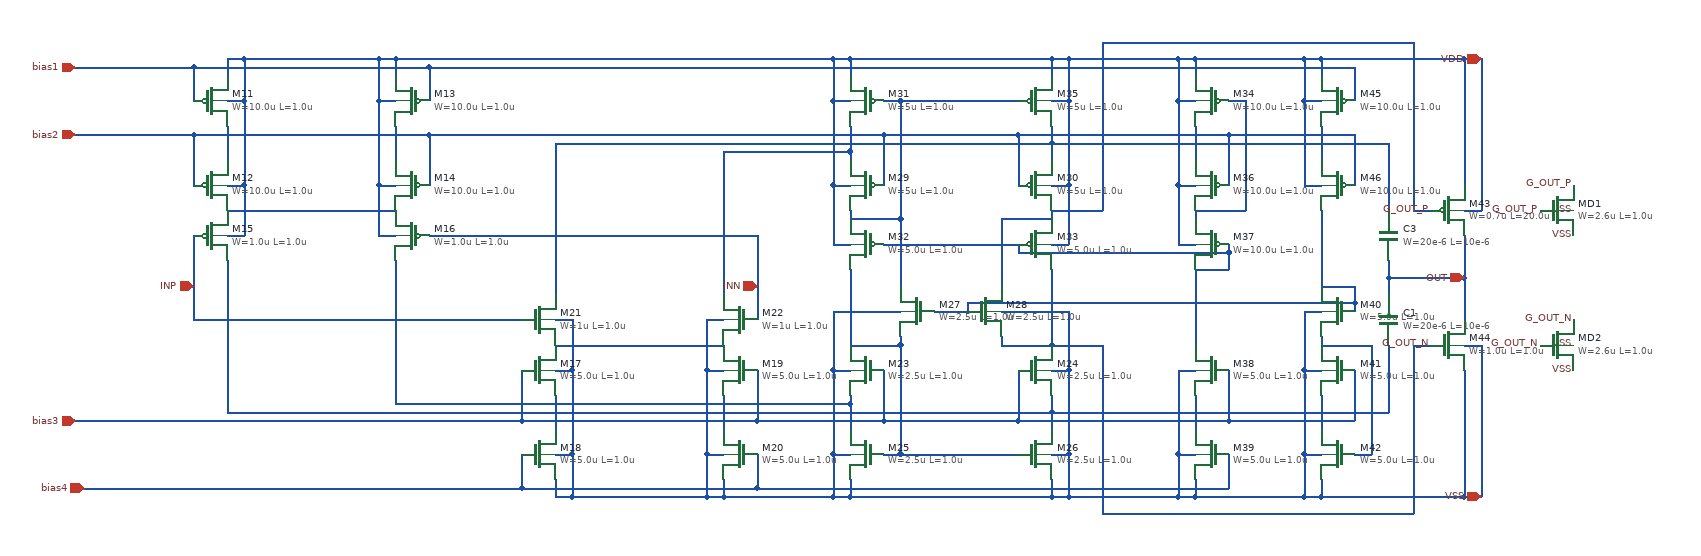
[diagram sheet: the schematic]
v {xschem version=3.4.8RC file_version=1.3}
G {}
K {}
V {}
S {}
F {}
E {}
N -580 -460 -560 -460 {
lab=VDD}
N -400 -460 -380 -460 {
lab=VDD}
N -580 -670 -580 -650 {
lab=VDD}
N -580 -620 -560 -620 {
lab=VDD}
N -620 -660 -620 -620 {
lab=bias1}
N 140 -200 140 -150 {
lab=VSS}
N 140 -200 160 -200 {
lab=VSS}
N 160 -170 160 -150 {
lab=VSS}
N 160 -670 160 -650 {
lab=VDD}
N 140 -620 160 -620 {
lab=VDD}
N 400 -670 400 -650 {
lab=VDD}
N 400 -620 420 -620 {
lab=VDD}
N 420 -620 420 -520 {
lab=VDD}
N 400 -200 420 -200 {
lab=VSS}
N 400 -170 400 -150 {
lab=VSS}
N -620 -460 -620 -360 {
lab=INP}
N -10 -360 10 -360 {
lab=VSS}
N -190 -300 -170 -300 {
lab=VSS}
N -170 -200 -170 -150 {
lab=VSS}
N -190 -200 -170 -200 {
lab=VSS}
N -190 -270 -190 -230 {
lab=#net1}
N -190 -170 -190 -150 {
lab=VSS}
N -230 -200 -230 -160 {
lab=#net2}
N -230 -300 -230 -240 {
lab=bias3}
N -580 -520 -560 -520 {
lab=VDD}
N -580 -590 -580 -550 {
lab=#net3}
N -620 -580 -620 -520 {
lab=bias2}
N 140 -620 140 -520 {
lab=VDD}
N 140 -520 160 -520 {
lab=VDD}
N 160 -560 160 -550 {
lab=#net4}
N 140 -300 160 -300 {
lab=VSS}
N 140 -300 140 -200 {
lab=VSS}
N 160 -260 160 -230 {
lab=#net5}
N 400 -250 400 -230 {
lab=#net6}
N 400 -300 420 -300 {
lab=VSS}
N -340 -460 50 -460 {
lab=INN}
N 50 -460 50 -360 {
lab=INN}
N 400 -520 420 -520 {
lab=VDD}
N 400 -570 400 -550 {
lab=#net7}
N -580 -490 -380 -490 {
lab=#net8}
N -620 -360 -230 -360 {
lab=INP}
N -190 -330 10 -330 {
lab=#net9}
N 160 -490 160 -480 {
lab=#net10}
N 140 -450 160 -450 {
lab=VDD}
N 140 -520 140 -450 {
lab=VDD}
N 220 -200 360 -200 {
lab=#net11}
N 420 -200 420 -150 {
lab=VSS}
N 260 -370 300 -370 {
lab=#net12}
N 400 -450 420 -450 {
lab=VDD}
N 420 -520 420 -450 {
lab=VDD}
N 400 -490 400 -480 {
lab=#net13}
N 340 -370 420 -370 {
lab=VSS}
N 420 -370 420 -300 {
lab=VSS}
N 890 -410 890 -360 {
lab=OUT}
N 890 -490 910 -490 {
lab=VDD}
N 910 -670 910 -490 {
lab=VDD}
N 570 -670 700 -670 {
lab=VDD}
N 890 -330 910 -330 {
lab=VSS}
N 910 -330 910 -150 {
lab=VSS}
N 890 -300 890 -150 {
lab=VSS}
N 890 -670 890 -520 {
lab=VDD}
N 550 -620 570 -620 {
lab=VDD}
N 550 -670 550 -620 {
lab=VDD}
N 570 -670 570 -650 {
lab=VDD}
N 570 -590 570 -550 {
lab=#net14}
N 550 -520 570 -520 {
lab=VDD}
N 550 -620 550 -520 {
lab=VDD}
N 570 -490 570 -480 {
lab=#net15}
N 550 -450 570 -450 {
lab=VDD}
N 550 -520 550 -450 {
lab=VDD}
N 550 -300 570 -300 {
lab=VSS}
N 550 -200 550 -150 {
lab=VSS}
N 550 -200 570 -200 {
lab=VSS}
N 570 -270 570 -230 {
lab=#net16}
N 570 -170 570 -150 {
lab=VSS}
N 610 -200 610 -160 {
lab=#net2}
N 610 -300 610 -240 {
lab=bias3}
N 700 -620 720 -620 {
lab=VDD}
N 700 -670 700 -620 {
lab=VDD}
N 720 -670 720 -650 {
lab=VDD}
N 720 -590 720 -550 {
lab=#net17}
N 700 -520 720 -520 {
lab=VDD}
N 700 -620 700 -520 {
lab=VDD}
N 700 -300 720 -300 {
lab=VSS}
N 700 -200 700 -150 {
lab=VSS}
N 700 -200 720 -200 {
lab=VSS}
N 720 -270 720 -230 {
lab=#net18}
N 720 -170 720 -150 {
lab=VSS}
N 720 -340 720 -330 {
lab=#net19}
N 700 -370 720 -370 {
lab=VSS}
N 700 -370 700 -300 {
lab=VSS}
N 720 -670 890 -670 {
lab=VDD}
N -380 -670 -380 -650 {
lab=VDD}
N -400 -620 -380 -620 {
lab=VDD}
N -340 -660 -340 -620 {
lab=bias1}
N -400 -520 -380 -520 {
lab=VDD}
N -380 -590 -380 -550 {
lab=#net20}
N -340 -580 -340 -520 {
lab=bias2}
N -10 -300 10 -300 {
lab=VSS}
N -10 -200 10 -200 {
lab=VSS}
N 10 -270 10 -230 {
lab=#net21}
N 10 -170 10 -150 {
lab=VSS}
N 50 -200 50 -160 {
lab=#net2}
N 50 -300 50 -240 {
lab=bias3}
N -190 -360 -170 -360 {
lab=VSS}
N 610 -580 610 -520 {
lab=bias2}
N 610 -620 630 -620 {
lab=#net15}
N 630 -620 630 -490 {
lab=#net15}
N 570 -490 630 -490 {
lab=#net15}
N 610 -440 610 -420 {
lab=#net22}
N 570 -420 610 -420 {
lab=#net22}
N 570 -420 570 -330 {
lab=#net22}
N 760 -660 760 -620 {
lab=bias1}
N 760 -580 760 -520 {
lab=bias2}
N 360 -240 610 -240 {
lab=bias3}
N 760 -300 760 -240 {
lab=bias3}
N 760 -200 780 -200 {
lab=#net19}
N 780 -330 780 -200 {
lab=#net19}
N 720 -330 780 -330 {
lab=#net19}
N 760 -380 760 -370 {
lab=#net12}
N 720 -400 760 -400 {
lab=#net12}
N 720 -490 720 -400 {
lab=#net12}
N 220 -620 360 -620 {
lab=#net10}
N 200 -580 200 -520 {
lab=bias2}
N 360 -580 360 -520 {
lab=bias2}
N 200 -450 360 -450 {
lab=#net22}
N 160 -420 160 -330 {
lab=#net11}
N 220 -340 220 -330 {
lab=#net11}
N 160 -330 220 -330 {
lab=#net11}
N 340 -340 340 -330 {
lab=#net23}
N 340 -330 400 -330 {
lab=#net23}
N 140 -370 220 -370 {
lab=VSS}
N 140 -370 140 -300 {
lab=VSS}
N 400 -420 400 -330 {
lab=#net23}
N 220 -480 220 -400 {
lab=#net10}
N 160 -480 220 -480 {
lab=#net10}
N 340 -480 340 -400 {
lab=#net13}
N 340 -480 400 -480 {
lab=#net13}
N 610 -580 760 -580 {
lab=bias2}
N 50 -160 610 -160 {
lab=#net2}
N 610 -240 760 -240 {
lab=bias3}
N 360 -440 610 -440 {
lab=#net22}
N 360 -450 360 -440 {
lab=#net22}
N 300 -380 760 -380 {
lab=#net12}
N 300 -380 300 -370 {
lab=#net12}
N -580 -430 -580 -250 {
lab=#net6}
N -380 -430 -380 -260 {
lab=#net5}
N -190 -570 -190 -390 {
lab=#net7}
N 10 -560 10 -390 {
lab=#net4}
N 200 -300 200 -240 {
lab=bias3}
N 360 -300 360 -240 {
lab=bias3}
N 220 -330 220 -200 {
lab=#net11}
N 220 -620 220 -480 {
lab=#net10}
N 890 -670 910 -670 {
lab=VDD}
N 830 -490 850 -490 {
lab=#net13}
N 830 -690 830 -490 {
lab=#net13}
N 460 -690 830 -690 {
lab=#net13}
N 460 -690 460 -490 {
lab=#net13}
N 400 -490 460 -490 {
lab=#net13}
N 830 -330 850 -330 {
lab=#net23}
N 830 -330 830 -130 {
lab=#net23}
N 460 -130 830 -130 {
lab=#net23}
N 460 -330 460 -130 {
lab=#net23}
N 400 -330 460 -330 {
lab=#net23}
N 400 -250 800 -250 {
lab=#net6}
N 800 -410 800 -390 {
lab=OUT}
N -190 -570 400 -570 {
lab=#net7}
N 10 -560 160 -560 {
lab=#net4}
N -380 -260 160 -260 {
lab=#net5}
N -580 -250 400 -250 {
lab=#net6}
N 140 -670 160 -670 {
lab=VDD}
N 400 -670 420 -670 {
lab=VDD}
N 890 -150 910 -150 {
lab=VSS}
N -230 -240 50 -240 {
lab=bias3}
N -230 -160 50 -160 {
lab=#net2}
N -620 -660 -340 -660 {
lab=bias1}
N -620 -580 -340 -580 {
lab=bias2}
N 360 -580 610 -580 {
lab=bias2}
N -340 -660 760 -660 {
lab=bias1}
N -400 -670 -380 -670 {
lab=VDD}
N -770 -660 -620 -660 {
lab=bias1}
N -770 -580 -620 -580 {
lab=bias2}
N -770 -240 -230 -240 {
lab=bias3}
N -750 -160 -230 -160 {
lab=#net2}
N 800 -410 890 -410 {
lab=OUT}
N 800 -330 800 -250 {
lab=#net6}
N 400 -570 800 -570 {
lab=#net7}
N 800 -570 800 -490 {
lab=#net7}
N 800 -430 800 -410 {
lab=OUT}
N -400 -620 -400 -520 {
lab=VDD}
N -560 -620 -560 -520 {
lab=VDD}
N -10 -200 -10 -150 {
lab=VSS}
N -170 -360 -170 -300 {
lab=VSS}
N -10 -360 -10 -300 {
lab=VSS}
N -560 -520 -560 -460 {
lab=VDD}
N -400 -520 -400 -460 {
lab=VDD}
N -560 -670 -560 -620 {
lab=VDD}
N 10 -150 140 -150 {
lab=VSS}
N 140 -150 160 -150 {
lab=VSS}
N 140 -670 140 -620 {
lab=VDD}
N 160 -670 400 -670 {
lab=VDD}
N 420 -670 420 -620 {
lab=VDD}
N 420 -300 420 -200 {
lab=VSS}
N 160 -150 400 -150 {
lab=VSS}
N -190 -150 -170 -150 {
lab=VSS}
N -170 -300 -170 -200 {
lab=VSS}
N 400 -150 420 -150 {
lab=VSS}
N 720 -150 890 -150 {
lab=VSS}
N 420 -670 550 -670 {
lab=VDD}
N 550 -670 570 -670 {
lab=VDD}
N 420 -150 550 -150 {
lab=VSS}
N 550 -300 550 -200 {
lab=VSS}
N 550 -150 570 -150 {
lab=VSS}
N 700 -670 720 -670 {
lab=VDD}
N 570 -150 700 -150 {
lab=VSS}
N 700 -300 700 -200 {
lab=VSS}
N 700 -150 720 -150 {
lab=VSS}
N -400 -670 -400 -620 {
lab=VDD}
N -10 -300 -10 -200 {
lab=VSS}
N -10 -150 10 -150 {
lab=VSS}
N -340 -580 200 -580 {
lab=bias2}
N 200 -580 360 -580 {
lab=bias2}
N 610 -450 610 -440 {
lab=#net22}
N 760 -400 760 -380 {
lab=#net12}
N 50 -240 200 -240 {
lab=bias3}
N 200 -240 360 -240 {
lab=bias3}
N 200 -200 220 -200 {
lab=#net11}
N 200 -620 220 -620 {
lab=#net10}
N 400 -270 400 -250 {
lab=#net6}
N 400 -590 400 -570 {
lab=#net7}
N 160 -590 160 -560 {
lab=#net4}
N 160 -270 160 -260 {
lab=#net5}
N 890 -460 890 -410 {
lab=OUT}
N -170 -150 -10 -150 {
lab=VSS}
N -580 -670 -560 -670 {
lab=VDD}
N -380 -670 140 -670 {
lab=VDD}
N -560 -670 -400 -670 {
lab=VDD}
C {ipin.sym} 50 -400 2 0 {name=p1 lab=INN}
C {ipin.sym} -620 -400 0 0 {name=p2 lab=INP}
C {iopin.sym} 910 -670 0 0 {name=p3 lab=VDD}
C {iopin.sym} 910 -150 0 0 {name=p4 lab=VSS}
C {iopin.sym} 890 -410 0 0 {name=p5 lab=OUT}
C {symbols/pfet_06v0.sym} -600 -620 0 0 {name=M11
L=1.0u
W=10.0u
nf=1
m=1
ad="'int((nf+1)/2) * W/nf * 0.18u'"
pd="'2*int((nf+1)/2) * (W/nf + 0.18u)'"
as="'int((nf+2)/2) * W/nf * 0.18u'"
ps="'2*int((nf+2)/2) * (W/nf + 0.18u)'"
nrd="'0.18u / W'" nrs="'0.18u / W'"
sa=0 sb=0 sd=0
model=pfet_06v0
spiceprefix=X
}
C {symbols/pfet_06v0.sym} -600 -520 0 0 {name=M12
L=1.0u
W=10.0u
nf=1
m=1
ad="'int((nf+1)/2) * W/nf * 0.18u'"
pd="'2*int((nf+1)/2) * (W/nf + 0.18u)'"
as="'int((nf+2)/2) * W/nf * 0.18u'"
ps="'2*int((nf+2)/2) * (W/nf + 0.18u)'"
nrd="'0.18u / W'" nrs="'0.18u / W'"
sa=0 sb=0 sd=0
model=pfet_06v0
spiceprefix=X
}
C {symbols/pfet_06v0.sym} -360 -620 0 1 {name=M13
L=1.0u
W=10.0u
nf=1
m=1
ad="'int((nf+1)/2) * W/nf * 0.18u'"
pd="'2*int((nf+1)/2) * (W/nf + 0.18u)'"
as="'int((nf+2)/2) * W/nf * 0.18u'"
ps="'2*int((nf+2)/2) * (W/nf + 0.18u)'"
nrd="'0.18u / W'" nrs="'0.18u / W'"
sa=0 sb=0 sd=0
model=pfet_06v0
spiceprefix=X
}
C {symbols/pfet_06v0.sym} -360 -520 0 1 {name=M14
L=1.0u
W=10.0u
nf=1
m=1
ad="'int((nf+1)/2) * W/nf * 0.18u'"
pd="'2*int((nf+1)/2) * (W/nf + 0.18u)'"
as="'int((nf+2)/2) * W/nf * 0.18u'"
ps="'2*int((nf+2)/2) * (W/nf + 0.18u)'"
nrd="'0.18u / W'" nrs="'0.18u / W'"
sa=0 sb=0 sd=0
model=pfet_06v0
spiceprefix=X
}
C {symbols/pfet_06v0.sym} -600 -460 0 0 {name=M15
L=1.0u
W=1.0u
nf=1
m=1
ad="'int((nf+1)/2) * W/nf * 0.18u'"
pd="'2*int((nf+1)/2) * (W/nf + 0.18u)'"
as="'int((nf+2)/2) * W/nf * 0.18u'"
ps="'2*int((nf+2)/2) * (W/nf + 0.18u)'"
nrd="'0.18u / W'" nrs="'0.18u / W'"
sa=0 sb=0 sd=0
model=pfet_06v0
spiceprefix=X
}
C {symbols/pfet_06v0.sym} -360 -460 0 1 {name=M16
L=1.0u
W=1.0u
nf=1
m=1
ad="'int((nf+1)/2) * W/nf * 0.18u'"
pd="'2*int((nf+1)/2) * (W/nf + 0.18u)'"
as="'int((nf+2)/2) * W/nf * 0.18u'"
ps="'2*int((nf+2)/2) * (W/nf + 0.18u)'"
nrd="'0.18u / W'" nrs="'0.18u / W'"
sa=0 sb=0 sd=0
model=pfet_06v0
spiceprefix=X
}
C {symbols/nfet_06v0.sym} -210 -300 0 0 {name=M17
L=1.0u
W=5.0u
nf=1
m=1
ad="'int((nf+1)/2) * W/nf * 0.18u'"
pd="'2*int((nf+1)/2) * (W/nf + 0.18u)'"
as="'int((nf+2)/2) * W/nf * 0.18u'"
ps="'2*int((nf+2)/2) * (W/nf + 0.18u)'"
nrd="'0.18u / W'" nrs="'0.18u / W'"
sa=0 sb=0 sd=0
model=nfet_06v0
spiceprefix=X
}
C {symbols/nfet_06v0.sym} -210 -200 0 0 {name=M18
L=1.0u
W=5.0u
nf=1
m=1
ad="'int((nf+1)/2) * W/nf * 0.18u'"
pd="'2*int((nf+1)/2) * (W/nf + 0.18u)'"
as="'int((nf+2)/2) * W/nf * 0.18u'"
ps="'2*int((nf+2)/2) * (W/nf + 0.18u)'"
nrd="'0.18u / W'" nrs="'0.18u / W'"
sa=0 sb=0 sd=0
model=nfet_06v0
spiceprefix=X
}
C {symbols/nfet_06v0.sym} 30 -300 0 1 {name=M19
L=1.0u
W=5.0u
nf=1
m=1
ad="'int((nf+1)/2) * W/nf * 0.18u'"
pd="'2*int((nf+1)/2) * (W/nf + 0.18u)'"
as="'int((nf+2)/2) * W/nf * 0.18u'"
ps="'2*int((nf+2)/2) * (W/nf + 0.18u)'"
nrd="'0.18u / W'" nrs="'0.18u / W'"
sa=0 sb=0 sd=0
model=nfet_06v0
spiceprefix=X
}
C {symbols/nfet_06v0.sym} 30 -200 0 1 {name=M20
L=1.0u
W=5.0u
nf=1
m=1
ad="'int((nf+1)/2) * W/nf * 0.18u'"
pd="'2*int((nf+1)/2) * (W/nf + 0.18u)'"
as="'int((nf+2)/2) * W/nf * 0.18u'"
ps="'2*int((nf+2)/2) * (W/nf + 0.18u)'"
nrd="'0.18u / W'" nrs="'0.18u / W'"
sa=0 sb=0 sd=0
model=nfet_06v0
spiceprefix=X
}
C {symbols/nfet_06v0.sym} -210 -360 0 0 {name=M21
L=1.0u
W=1u
nf=1
m=1
ad="'int((nf+1)/2) * W/nf * 0.18u'"
pd="'2*int((nf+1)/2) * (W/nf + 0.18u)'"
as="'int((nf+2)/2) * W/nf * 0.18u'"
ps="'2*int((nf+2)/2) * (W/nf + 0.18u)'"
nrd="'0.18u / W'" nrs="'0.18u / W'"
sa=0 sb=0 sd=0
model=nfet_06v0
spiceprefix=X
}
C {symbols/nfet_06v0.sym} 30 -360 0 1 {name=M22
L=1.0u
W=1u
nf=1
m=1
ad="'int((nf+1)/2) * W/nf * 0.18u'"
pd="'2*int((nf+1)/2) * (W/nf + 0.18u)'"
as="'int((nf+2)/2) * W/nf * 0.18u'"
ps="'2*int((nf+2)/2) * (W/nf + 0.18u)'"
nrd="'0.18u / W'" nrs="'0.18u / W'"
sa=0 sb=0 sd=0
model=nfet_06v0
spiceprefix=X
}
C {symbols/pfet_06v0.sym} 180 -520 0 1 {name=M29
L=1.0u
W=5u
nf=1
m=1
ad="'int((nf+1)/2) * W/nf * 0.18u'"
pd="'2*int((nf+1)/2) * (W/nf + 0.18u)'"
as="'int((nf+2)/2) * W/nf * 0.18u'"
ps="'2*int((nf+2)/2) * (W/nf + 0.18u)'"
nrd="'0.18u / W'" nrs="'0.18u / W'"
sa=0 sb=0 sd=0
model=pfet_06v0
spiceprefix=X
}
C {symbols/pfet_06v0.sym} 380 -520 0 0 {name=M30
L=1.0u
W=5u
nf=1
m=1
ad="'int((nf+1)/2) * W/nf * 0.18u'"
pd="'2*int((nf+1)/2) * (W/nf + 0.18u)'"
as="'int((nf+2)/2) * W/nf * 0.18u'"
ps="'2*int((nf+2)/2) * (W/nf + 0.18u)'"
nrd="'0.18u / W'" nrs="'0.18u / W'"
sa=0 sb=0 sd=0
model=pfet_06v0
spiceprefix=X
}
C {symbols/pfet_06v0.sym} 180 -620 0 1 {name=M31
L=1.0u
W=5u
nf=1
m=1
ad="'int((nf+1)/2) * W/nf * 0.18u'"
pd="'2*int((nf+1)/2) * (W/nf + 0.18u)'"
as="'int((nf+2)/2) * W/nf * 0.18u'"
ps="'2*int((nf+2)/2) * (W/nf + 0.18u)'"
nrd="'0.18u / W'" nrs="'0.18u / W'"
sa=0 sb=0 sd=0
model=pfet_06v0
spiceprefix=X
}
C {symbols/pfet_06v0.sym} 380 -620 0 0 {name=M35
L=1.0u
W=5u
nf=1
m=1
ad="'int((nf+1)/2) * W/nf * 0.18u'"
pd="'2*int((nf+1)/2) * (W/nf + 0.18u)'"
as="'int((nf+2)/2) * W/nf * 0.18u'"
ps="'2*int((nf+2)/2) * (W/nf + 0.18u)'"
nrd="'0.18u / W'" nrs="'0.18u / W'"
sa=0 sb=0 sd=0
model=pfet_06v0
spiceprefix=X
}
C {symbols/pfet_06v0.sym} 180 -450 0 1 {name=M32
L=1.0u
W=5.0u
nf=1
m=1
ad="'int((nf+1)/2) * W/nf * 0.18u'"
pd="'2*int((nf+1)/2) * (W/nf + 0.18u)'"
as="'int((nf+2)/2) * W/nf * 0.18u'"
ps="'2*int((nf+2)/2) * (W/nf + 0.18u)'"
nrd="'0.18u / W'" nrs="'0.18u / W'"
sa=0 sb=0 sd=0
model=pfet_06v0
spiceprefix=X
}
C {symbols/pfet_06v0.sym} 380 -450 0 0 {name=M33
L=1.0u
W=5.0u
nf=1
m=1
ad="'int((nf+1)/2) * W/nf * 0.18u'"
pd="'2*int((nf+1)/2) * (W/nf + 0.18u)'"
as="'int((nf+2)/2) * W/nf * 0.18u'"
ps="'2*int((nf+2)/2) * (W/nf + 0.18u)'"
nrd="'0.18u / W'" nrs="'0.18u / W'"
sa=0 sb=0 sd=0
model=pfet_06v0
spiceprefix=X
}
C {symbols/nfet_06v0.sym} 180 -300 0 1 {name=M23
L=1.0u
W=2.5u
nf=1
m=1
ad="'int((nf+1)/2) * W/nf * 0.18u'"
pd="'2*int((nf+1)/2) * (W/nf + 0.18u)'"
as="'int((nf+2)/2) * W/nf * 0.18u'"
ps="'2*int((nf+2)/2) * (W/nf + 0.18u)'"
nrd="'0.18u / W'" nrs="'0.18u / W'"
sa=0 sb=0 sd=0
model=nfet_06v0
spiceprefix=X
}
C {symbols/nfet_06v0.sym} 380 -300 0 0 {name=M24
L=1.0u
W=2.5u
nf=1
m=1
ad="'int((nf+1)/2) * W/nf * 0.18u'"
pd="'2*int((nf+1)/2) * (W/nf + 0.18u)'"
as="'int((nf+2)/2) * W/nf * 0.18u'"
ps="'2*int((nf+2)/2) * (W/nf + 0.18u)'"
nrd="'0.18u / W'" nrs="'0.18u / W'"
sa=0 sb=0 sd=0
model=nfet_06v0
spiceprefix=X
}
C {symbols/nfet_06v0.sym} 180 -200 0 1 {name=M25
L=1.0u
W=2.5u
nf=1
m=1
ad="'int((nf+1)/2) * W/nf * 0.18u'"
pd="'2*int((nf+1)/2) * (W/nf + 0.18u)'"
as="'int((nf+2)/2) * W/nf * 0.18u'"
ps="'2*int((nf+2)/2) * (W/nf + 0.18u)'"
nrd="'0.18u / W'" nrs="'0.18u / W'"
sa=0 sb=0 sd=0
model=nfet_06v0
spiceprefix=X
}
C {symbols/nfet_06v0.sym} 380 -200 0 0 {name=M26
L=1.0u
W=2.5u
nf=1
m=1
ad="'int((nf+1)/2) * W/nf * 0.18u'"
pd="'2*int((nf+1)/2) * (W/nf + 0.18u)'"
as="'int((nf+2)/2) * W/nf * 0.18u'"
ps="'2*int((nf+2)/2) * (W/nf + 0.18u)'"
nrd="'0.18u / W'" nrs="'0.18u / W'"
sa=0 sb=0 sd=0
model=nfet_06v0
spiceprefix=X
}
C {symbols/nfet_06v0.sym} 240 -370 0 1 {name=M27
L=1.0u
W=2.5u
nf=1
m=1
ad="'int((nf+1)/2) * W/nf * 0.18u'"
pd="'2*int((nf+1)/2) * (W/nf + 0.18u)'"
as="'int((nf+2)/2) * W/nf * 0.18u'"
ps="'2*int((nf+2)/2) * (W/nf + 0.18u)'"
nrd="'0.18u / W'" nrs="'0.18u / W'"
sa=0 sb=0 sd=0
model=nfet_06v0
spiceprefix=X
}
C {symbols/nfet_06v0.sym} 320 -370 0 0 {name=M28
L=1.0u
W=2.5u
nf=1
m=1
ad="'int((nf+1)/2) * W/nf * 0.18u'"
pd="'2*int((nf+1)/2) * (W/nf + 0.18u)'"
as="'int((nf+2)/2) * W/nf * 0.18u'"
ps="'2*int((nf+2)/2) * (W/nf + 0.18u)'"
nrd="'0.18u / W'" nrs="'0.18u / W'"
sa=0 sb=0 sd=0
model=nfet_06v0
spiceprefix=X
}
C {symbols/pfet_06v0.sym} 590 -620 0 1 {name=M34
L=1.0u
W=10.0u
nf=1
m=1
ad="'int((nf+1)/2) * W/nf * 0.18u'"
pd="'2*int((nf+1)/2) * (W/nf + 0.18u)'"
as="'int((nf+2)/2) * W/nf * 0.18u'"
ps="'2*int((nf+2)/2) * (W/nf + 0.18u)'"
nrd="'0.18u / W'" nrs="'0.18u / W'"
sa=0 sb=0 sd=0
model=pfet_06v0
spiceprefix=X
}
C {symbols/pfet_06v0.sym} 590 -520 0 1 {name=M36
L=1.0u
W=10.0u
nf=1
m=1
ad="'int((nf+1)/2) * W/nf * 0.18u'"
pd="'2*int((nf+1)/2) * (W/nf + 0.18u)'"
as="'int((nf+2)/2) * W/nf * 0.18u'"
ps="'2*int((nf+2)/2) * (W/nf + 0.18u)'"
nrd="'0.18u / W'" nrs="'0.18u / W'"
sa=0 sb=0 sd=0
model=pfet_06v0
spiceprefix=X
}
C {symbols/pfet_06v0.sym} 590 -450 0 1 {name=M37
L=1.0u
W=10.0u
nf=1
m=1
ad="'int((nf+1)/2) * W/nf * 0.18u'"
pd="'2*int((nf+1)/2) * (W/nf + 0.18u)'"
as="'int((nf+2)/2) * W/nf * 0.18u'"
ps="'2*int((nf+2)/2) * (W/nf + 0.18u)'"
nrd="'0.18u / W'" nrs="'0.18u / W'"
sa=0 sb=0 sd=0
model=pfet_06v0
spiceprefix=X
}
C {symbols/nfet_06v0.sym} 590 -300 0 1 {name=M38
L=1.0u
W=5.0u
nf=1
m=1
ad="'int((nf+1)/2) * W/nf * 0.18u'"
pd="'2*int((nf+1)/2) * (W/nf + 0.18u)'"
as="'int((nf+2)/2) * W/nf * 0.18u'"
ps="'2*int((nf+2)/2) * (W/nf + 0.18u)'"
nrd="'0.18u / W'" nrs="'0.18u / W'"
sa=0 sb=0 sd=0
model=nfet_06v0
spiceprefix=X
}
C {symbols/nfet_06v0.sym} 590 -200 0 1 {name=M39
L=1.0u
W=5.0u
nf=1
m=1
ad="'int((nf+1)/2) * W/nf * 0.18u'"
pd="'2*int((nf+1)/2) * (W/nf + 0.18u)'"
as="'int((nf+2)/2) * W/nf * 0.18u'"
ps="'2*int((nf+2)/2) * (W/nf + 0.18u)'"
nrd="'0.18u / W'" nrs="'0.18u / W'"
sa=0 sb=0 sd=0
model=nfet_06v0
spiceprefix=X
}
C {symbols/pfet_06v0.sym} 740 -620 0 1 {name=M45
L=1.0u
W=10.0u
nf=1
m=1
ad="'int((nf+1)/2) * W/nf * 0.18u'"
pd="'2*int((nf+1)/2) * (W/nf + 0.18u)'"
as="'int((nf+2)/2) * W/nf * 0.18u'"
ps="'2*int((nf+2)/2) * (W/nf + 0.18u)'"
nrd="'0.18u / W'" nrs="'0.18u / W'"
sa=0 sb=0 sd=0
model=pfet_06v0
spiceprefix=X
}
C {symbols/pfet_06v0.sym} 740 -520 0 1 {name=M46
L=1.0u
W=10.0u
nf=1
m=1
ad="'int((nf+1)/2) * W/nf * 0.18u'"
pd="'2*int((nf+1)/2) * (W/nf + 0.18u)'"
as="'int((nf+2)/2) * W/nf * 0.18u'"
ps="'2*int((nf+2)/2) * (W/nf + 0.18u)'"
nrd="'0.18u / W'" nrs="'0.18u / W'"
sa=0 sb=0 sd=0
model=pfet_06v0
spiceprefix=X
}
C {symbols/nfet_06v0.sym} 740 -370 0 1 {name=M40
L=1.0u
W=5.0u
nf=1
m=1
ad="'int((nf+1)/2) * W/nf * 0.18u'"
pd="'2*int((nf+1)/2) * (W/nf + 0.18u)'"
as="'int((nf+2)/2) * W/nf * 0.18u'"
ps="'2*int((nf+2)/2) * (W/nf + 0.18u)'"
nrd="'0.18u / W'" nrs="'0.18u / W'"
sa=0 sb=0 sd=0
model=nfet_06v0
spiceprefix=X
}
C {symbols/nfet_06v0.sym} 740 -300 0 1 {name=M41
L=1.0u
W=5.0u
nf=1
m=1
ad="'int((nf+1)/2) * W/nf * 0.18u'"
pd="'2*int((nf+1)/2) * (W/nf + 0.18u)'"
as="'int((nf+2)/2) * W/nf * 0.18u'"
ps="'2*int((nf+2)/2) * (W/nf + 0.18u)'"
nrd="'0.18u / W'" nrs="'0.18u / W'"
sa=0 sb=0 sd=0
model=nfet_06v0
spiceprefix=X
}
C {symbols/nfet_06v0.sym} 740 -200 0 1 {name=M42
L=1.0u
W=5.0u
nf=1
m=1
ad="'int((nf+1)/2) * W/nf * 0.18u'"
pd="'2*int((nf+1)/2) * (W/nf + 0.18u)'"
as="'int((nf+2)/2) * W/nf * 0.18u'"
ps="'2*int((nf+2)/2) * (W/nf + 0.18u)'"
nrd="'0.18u / W'" nrs="'0.18u / W'"
sa=0 sb=0 sd=0
model=nfet_06v0
spiceprefix=X
}
C {symbols/pfet_06v0.sym} 870 -490 0 0 {name=M43
L=20.0u
W=0.7u
nf=1
m=1
ad="'int((nf+1)/2) * W/nf * 0.18u'"
pd="'2*int((nf+1)/2) * (W/nf + 0.18u)'"
as="'int((nf+2)/2) * W/nf * 0.18u'"
ps="'2*int((nf+2)/2) * (W/nf + 0.18u)'"
nrd="'0.18u / W'" nrs="'0.18u / W'"
sa=0 sb=0 sd=0
model=pfet_06v0
spiceprefix=X
}
C {symbols/nfet_06v0.sym} 870 -330 0 0 {name=M44
L=1.0u
W=1.0u
nf=1
m=1
ad="'int((nf+1)/2) * W/nf * 0.18u'"
pd="'2*int((nf+1)/2) * (W/nf + 0.18u)'"
as="'int((nf+2)/2) * W/nf * 0.18u'"
ps="'2*int((nf+2)/2) * (W/nf + 0.18u)'"
nrd="'0.18u / W'" nrs="'0.18u / W'"
sa=0 sb=0 sd=0
model=nfet_06v0
spiceprefix=X
}
C {symbols/cap_mim_2f0fF.sym} 800 -460 0 0 {name=C3
W=20e-6
L=10e-6
model=cap_mim_2f0fF
spiceprefix=X
m=1}
C {symbols/cap_mim_2f0fF.sym} 800 -360 0 0 {name=C1
W=20e-6
L=10e-6
model=cap_mim_2f0fF
spiceprefix=X
m=1}
C {devices/ipin.sym} -760 -660 0 0 {name=p6 lab=bias1}
C {devices/ipin.sym} -760 -580 0 0 {name=p7 lab=bias2}
C {devices/ipin.sym} -760 -240 0 0 {name=p8 lab=bias3}
C {devices/ipin.sym} -750 -160 0 0 {name=p9 lab=bias4}
C {devices/lab_pin.sym} 850 -490 0 0 {name=pMD10 sig_type=std_logic lab=G_OUT_P}
C {devices/lab_pin.sym} 980 -490 0 0 {name=pMD11 sig_type=std_logic lab=G_OUT_P}
C {devices/lab_pin.sym} 1020 -520 0 0 {name=pMD12 sig_type=std_logic lab=G_OUT_P}
C {devices/lab_pin.sym} 1020 -460 0 0 {name=pMD13 sig_type=std_logic lab=VSS}
C {devices/lab_pin.sym} 1020 -490 0 0 {name=pMD14 sig_type=std_logic lab=VSS}
C {symbols/nfet_06v0.sym} 1000 -490 0 0 {name=MD1
L=1.0u
W=2.6u
nf=1
m=1
ad="'int((nf+1)/2) * W/nf * 0.18u'"
pd="'2*int((nf+1)/2) * (W/nf + 0.18u)'"
as="'int((nf+2)/2) * W/nf * 0.18u'"
ps="'2*int((nf+2)/2) * (W/nf + 0.18u)'"
nrd="'0.18u / W'" nrs="'0.18u / W'"
sa=0 sb=0 sd=0
model=nfet_06v0
spiceprefix=X
}
C {devices/lab_pin.sym} 850 -330 0 0 {name=pMD20 sig_type=std_logic lab=G_OUT_N}
C {devices/lab_pin.sym} 980 -330 0 0 {name=pMD21 sig_type=std_logic lab=G_OUT_N}
C {devices/lab_pin.sym} 1020 -360 0 0 {name=pMD22 sig_type=std_logic lab=G_OUT_N}
C {devices/lab_pin.sym} 1020 -300 0 0 {name=pMD23 sig_type=std_logic lab=VSS}
C {devices/lab_pin.sym} 1020 -330 0 0 {name=pMD24 sig_type=std_logic lab=VSS}
C {symbols/nfet_06v0.sym} 1000 -330 0 0 {name=MD2
L=1.0u
W=2.6u
nf=1
m=1
ad="'int((nf+1)/2) * W/nf * 0.18u'"
pd="'2*int((nf+1)/2) * (W/nf + 0.18u)'"
as="'int((nf+2)/2) * W/nf * 0.18u'"
ps="'2*int((nf+2)/2) * (W/nf + 0.18u)'"
nrd="'0.18u / W'" nrs="'0.18u / W'"
sa=0 sb=0 sd=0
model=nfet_06v0
spiceprefix=X
}
